One B-rep face of a CAD part: STEP entity #908.
In plain terms, the planar face has unit normal (1, 0, 0).
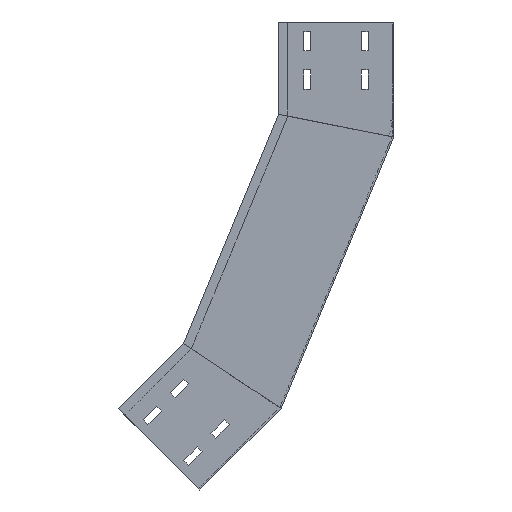
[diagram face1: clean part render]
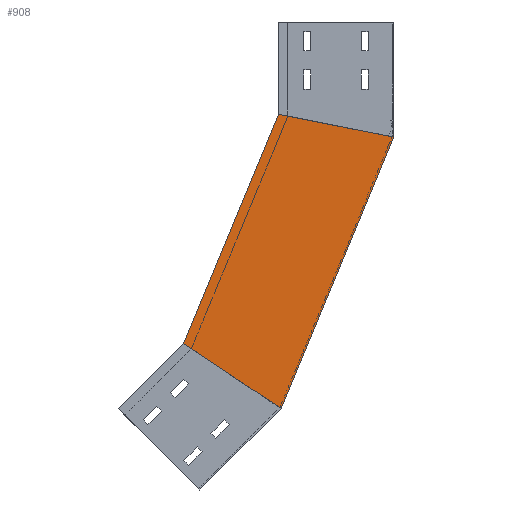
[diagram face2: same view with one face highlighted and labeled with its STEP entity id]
Its self-contained STEP definition (entity closure, numbers rounded to 3 decimals):
#32 = EDGE_CURVE ( 'NONE', #1106, #1805, #384, .T. ) ;
#157 = VECTOR ( 'NONE', #1940, 1000. ) ;
#183 = EDGE_CURVE ( 'NONE', #623, #1416, #1702, .T. ) ;
#287 = DIRECTION ( 'NONE',  ( 0., -0.831, -0.556 ) ) ;
#288 = ORIENTED_EDGE ( 'NONE', *, *, #32, .T. ) ;
#318 = VECTOR ( 'NONE', #1939, 1000. ) ;
#330 = LINE ( 'NONE', #488, #157 ) ;
#333 = CARTESIAN_POINT ( 'NONE',  ( 0., 0., -150. ) ) ;
#384 = LINE ( 'NONE', #1018, #318 ) ;
#426 = AXIS2_PLACEMENT_3D ( 'NONE', #1093, #2009, #1390 ) ;
#488 = CARTESIAN_POINT ( 'NONE',  ( 0., 138.582, -92.597 ) ) ;
#594 = PLANE ( 'NONE',  #426 ) ;
#623 = VERTEX_POINT ( 'NONE', #1144 ) ;
#647 = EDGE_CURVE ( 'NONE', #1805, #1416, #1912, .T. ) ;
#890 = VECTOR ( 'NONE', #287, 1000. ) ;
#908 = ADVANCED_FACE ( 'NONE', ( #1738 ), #594, .F. ) ;
#969 = DIRECTION ( 'NONE',  ( 0., 0.383, -0.924 ) ) ;
#1008 = EDGE_CURVE ( 'NONE', #1106, #623, #330, .T. ) ;
#1011 = ORIENTED_EDGE ( 'NONE', *, *, #183, .F. ) ;
#1013 = CARTESIAN_POINT ( 'NONE',  ( 0., 0., -150. ) ) ;
#1018 = CARTESIAN_POINT ( 'NONE',  ( 0., 28.701, -144.291 ) ) ;
#1093 = CARTESIAN_POINT ( 'NONE',  ( 0., 0., -150. ) ) ;
#1106 = VERTEX_POINT ( 'NONE', #1200 ) ;
#1144 = CARTESIAN_POINT ( 'NONE',  ( 0., 273.732, -418.878 ) ) ;
#1196 = ORIENTED_EDGE ( 'NONE', *, *, #647, .T. ) ;
#1200 = CARTESIAN_POINT ( 'NONE',  ( 0., 150., -120.163 ) ) ;
#1390 = DIRECTION ( 'NONE',  ( 0., 0., 1. ) ) ;
#1416 = VERTEX_POINT ( 'NONE', #1992 ) ;
#1574 = EDGE_LOOP ( 'NONE', ( #1622, #288, #1196, #1011 ) ) ;
#1622 = ORIENTED_EDGE ( 'NONE', *, *, #1008, .F. ) ;
#1702 = LINE ( 'NONE', #1848, #890 ) ;
#1738 = FACE_OUTER_BOUND ( 'NONE', #1574, .T. ) ;
#1805 = VERTEX_POINT ( 'NONE', #1013 ) ;
#1848 = CARTESIAN_POINT ( 'NONE',  ( 0., 208.695, -462.334 ) ) ;
#1912 = LINE ( 'NONE', #333, #1938 ) ;
#1938 = VECTOR ( 'NONE', #969, 1000. ) ;
#1939 = DIRECTION ( 'NONE',  ( 0., -0.981, -0.195 ) ) ;
#1940 = DIRECTION ( 'NONE',  ( 0., 0.383, -0.924 ) ) ;
#1992 = CARTESIAN_POINT ( 'NONE',  ( 0., 146.568, -503.846 ) ) ;
#2009 = DIRECTION ( 'NONE',  ( -1., 0., 0. ) ) ;
